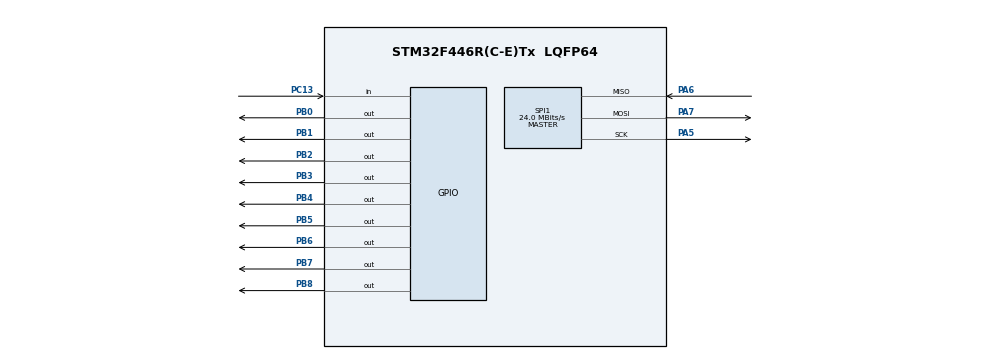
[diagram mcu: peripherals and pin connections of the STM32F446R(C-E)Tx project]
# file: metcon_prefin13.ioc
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Mcu.Family=STM32F4
Mcu.Name=STM32F446R(C-E)Tx
Mcu.Package=LQFP64
NVIC.PriorityGroup=NVIC_PRIORITYGROUP_4
PA5.Mode=Full_Duplex_Master
PA5.Signal=SPI1_SCK
PA6.Mode=Full_Duplex_Master
PA6.Signal=SPI1_MISO
PA7.Mode=Full_Duplex_Master
PA7.Signal=SPI1_MOSI
PB0.Signal=GPIO_Output
PB1.Signal=GPIO_Output
PB2.Signal=GPIO_Output
PB3.Signal=GPIO_Output
PB4.Signal=GPIO_Output
PB5.Signal=GPIO_Output
PB6.Signal=GPIO_Output
PB7.Signal=GPIO_Output
PB8.Signal=GPIO_Output
PC13.Signal=GPIO_Input
PH0-OSC_IN.Mode=HSE-External-Oscillator
PH0-OSC_IN.Signal=RCC_OSC_IN
PH1-OSC_OUT.Mode=HSE-External-Oscillator
PH1-OSC_OUT.Signal=RCC_OSC_OUT
ProjectManager.HeapSize=0x200
ProjectManager.StackSize=0x400
ProjectManager.TargetToolchain=STM32CubeIDE
RCC.AHBFreq_Value=48000000
RCC.APB1CLKDivider=RCC_HCLK_DIV2
RCC.APB1Freq_Value=24000000
RCC.APB1TimFreq_Value=48000000
RCC.APB2Freq_Value=48000000
RCC.APB2TimFreq_Value=48000000
RCC.CortexFreq_Value=48000000
RCC.HCLKFreq_Value=48000000
RCC.HSE_VALUE=8000000
RCC.PLLM=8
RCC.PLLP=RCC_PLLP_DIV4
RCC.PLLSourceVirtual=RCC_PLLSOURCE_HSE
RCC.SYSCLKFreq_VALUE=48000000
RCC.SYSCLKSource=RCC_SYSCLKSOURCE_PLLCLK
RCC.USBFreq_Value=96000000
RCC.VCOOutputFreq_Value=192000000
SPI1.CalculateBaudRate=24.0 MBits/s
SPI1.Direction=SPI_DIRECTION_2LINES
SPI1.Mode=SPI_MODE_MASTER
SPI1.VirtualType=VM_MASTER
board=custom

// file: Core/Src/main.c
/* USER CODE BEGIN Header */
/**
  ******************************************************************************
  * @file           : main.c
  * @brief          : Main program body
  ******************************************************************************
  * @attention
  *
  * Copyright (c) 2022 STMicroelectronics.
  * All rights reserved.
  *
  * This software is licensed under terms that can be found in the LICENSE file
  * in the root directory of this software component.
  * If no LICENSE file comes with this software, it is provided AS-IS.
  *
  ******************************************************************************
  */
/* USER CODE END Header */
#include "main.h"

/* USER CODE BEGIN Includes */
#include "functions.h"
#include "at45db_api.h"
/* USER CODE END Includes */

SPI_HandleTypeDef hspi1;

/* USER CODE BEGIN PV */
extern struct midi_msg incoming_note;
extern struct midi_msg incoming_CC_msg;
extern uint8_t msg_type;
extern uint8_t global_mode;

extern struct midi_msg incoming_note2;
extern struct midi_msg incoming_CC_msg2;
extern uint8_t msg_type2;

extern struct midi_msg seq_msg_list[WAITHEIGHT];					//array of sequencer messages need to be sensded.
extern uint8_t 		   seq_msg_push_index;
extern uint8_t 		   seq_msg_pop_index;
extern int 			   midi_access_semaph;
extern int 			   seq_list_flag;

/////////////////
extern struct midi_container 	sequencer_arr[SEQAMOUNT];				//array of sequencers
extern int 						seq_irq_cnt[SEQAMOUNT];

/* USER CODE END PV */

void SystemClock_Config(void);
static void MX_GPIO_Init(void);
static void MX_SPI1_Init(void);

int main(void)
{
  /* USER CODE BEGIN 1 */
	__disable_irq();
	SCB->VTOR = 0x08040000;
	__enable_irq();
  /* USER CODE END 1 */

  /* MCU Configuration--------------------------------------------------------*/

  /* Reset of all peripherals, Initializes the Flash interface and the Systick. */
  HAL_Init();

  /* Configure the system clock */
  SystemClock_Config();

  /* Initialize all configured peripherals */
  MX_GPIO_Init();
  MX_SPI1_Init();
  /* USER CODE BEGIN 2 */

  GPIO_Init();
  TIM1_Init_and_Start();
  EXTI_Init();
  usart1_init_and_start();
  usart2_init_and_start();
  usart3_init_and_start();
  usart4_init_and_start();

  GPIOB->ODR |= 1 << 9;  								//nWP   initial state
  GPIOB->ODR |= 1 << 10; 								//nCS   initial state

  global_mode_setting(); 								//endless cycle until user choose mode

  index_show_set();
  structures_init();

  /* USER CODE END 2 */

  /* Infinite loop */
  /* USER CODE BEGIN WHILE */
  while (1)
  {

	  // For Ornament Mode
	  for(int i = 0; i < SEQAMOUNT; i++)
	  {
		  if(seq_irq_cnt[i] > 0)
		  {
			  seq_irq_cnt[i]--;
			  real_pop_from_sequencer(&sequencer_arr[i], i);
		  }
	  }

	  empty_trig_queue(); // Эта очередь заполняется и секвенсором и сплиттером, когда отправляешь края диапазона

	  message_assambling();
	  if(incoming_note.complete_flag == 1)
	  {
		  incoming_note_processing(1);
	  }
	  if(incoming_CC_msg.complete_flag == 1)
	  {
		  incoming_CC_processing(1);
	  }

	  // Second midi in

	  message_assambling2();
	  if(incoming_note2.complete_flag == 1)
	  {
		  incoming_note_processing(2);
	  }
	  if(incoming_CC_msg2.complete_flag == 1)
	  {
		  incoming_CC_processing(2);
	  }

    /* USER CODE END WHILE */

  }
}

void SystemClock_Config(void)
{
  RCC_OscInitTypeDef RCC_OscInitStruct = {0};
  RCC_ClkInitTypeDef RCC_ClkInitStruct = {0};

  /** Configure the main internal regulator output voltage
  */
  __HAL_RCC_PWR_CLK_ENABLE();
  __HAL_PWR_VOLTAGESCALING_CONFIG(PWR_REGULATOR_VOLTAGE_SCALE3);
  /** Initializes the RCC Oscillators according to the specified parameters
  * in the RCC_OscInitTypeDef structure.
  */
  RCC_OscInitStruct.OscillatorType = RCC_OSCILLATORTYPE_HSE;
  RCC_OscInitStruct.HSEState = RCC_HSE_ON;
  RCC_OscInitStruct.PLL.PLLState = RCC_PLL_ON;
  RCC_OscInitStruct.PLL.PLLSource = RCC_PLLSOURCE_HSE;
  RCC_OscInitStruct.PLL.PLLM = 16; // 8 - for green, 16 - for black
  RCC_OscInitStruct.PLL.PLLN = 192;
  RCC_OscInitStruct.PLL.PLLP = RCC_PLLP_DIV4;
  RCC_OscInitStruct.PLL.PLLQ = 2;
  RCC_OscInitStruct.PLL.PLLR = 2;
  if (HAL_RCC_OscConfig(&RCC_OscInitStruct) != HAL_OK)
  {
    Error_Handler();
  }
  /** Initializes the CPU, AHB and APB buses clocks
  */
  RCC_ClkInitStruct.ClockType = RCC_CLOCKTYPE_HCLK|RCC_CLOCKTYPE_SYSCLK
                              |RCC_CLOCKTYPE_PCLK1|RCC_CLOCKTYPE_PCLK2;
  RCC_ClkInitStruct.SYSCLKSource = RCC_SYSCLKSOURCE_PLLCLK;
  RCC_ClkInitStruct.AHBCLKDivider = RCC_SYSCLK_DIV1;
  RCC_ClkInitStruct.APB1CLKDivider = RCC_HCLK_DIV2;
  RCC_ClkInitStruct.APB2CLKDivider = RCC_HCLK_DIV1;

  if (HAL_RCC_ClockConfig(&RCC_ClkInitStruct, FLASH_LATENCY_1) != HAL_OK)
  {
    Error_Handler();
  }
}

static void MX_SPI1_Init(void)
{

  /* SPI1 parameter configuration*/
  hspi1.Instance = SPI1;
  hspi1.Init.Mode = SPI_MODE_MASTER;
  hspi1.Init.Direction = SPI_DIRECTION_2LINES;
  hspi1.Init.DataSize = SPI_DATASIZE_8BIT;
  hspi1.Init.CLKPolarity = SPI_POLARITY_LOW;
  hspi1.Init.CLKPhase = SPI_PHASE_1EDGE;
  hspi1.Init.NSS = SPI_NSS_SOFT;
  hspi1.Init.BaudRatePrescaler = SPI_BAUDRATEPRESCALER_2;
  hspi1.Init.FirstBit = SPI_FIRSTBIT_MSB;
  hspi1.Init.TIMode = SPI_TIMODE_DISABLE;
  hspi1.Init.CRCCalculation = SPI_CRCCALCULATION_DISABLE;
  hspi1.Init.CRCPolynomial = 10;
  if (HAL_SPI_Init(&hspi1) != HAL_OK)
  {
    Error_Handler();
  }

}

static void MX_GPIO_Init(void)
{
  GPIO_InitTypeDef GPIO_InitStruct = {0};

  /* GPIO Ports Clock Enable */
  __HAL_RCC_GPIOC_CLK_ENABLE();
  __HAL_RCC_GPIOH_CLK_ENABLE();
  __HAL_RCC_GPIOA_CLK_ENABLE();
  __HAL_RCC_GPIOB_CLK_ENABLE();

  /*Configure GPIO pin Output Level */
  HAL_GPIO_WritePin(GPIOB, GPIO_PIN_0|GPIO_PIN_1|GPIO_PIN_2|GPIO_PIN_3
                          |GPIO_PIN_4|GPIO_PIN_5|GPIO_PIN_6|GPIO_PIN_7
                          |GPIO_PIN_8, GPIO_PIN_RESET);

  /*Configure GPIO pin : PC13 */
  GPIO_InitStruct.Pin = GPIO_PIN_13;
  GPIO_InitStruct.Mode = GPIO_MODE_INPUT;
  GPIO_InitStruct.Pull = GPIO_NOPULL;
  HAL_GPIO_Init(GPIOC, &GPIO_InitStruct);

  /*Configure GPIO pins : PB0 PB1 PB2 PB3
                           PB4 PB5 PB6 PB7
                           PB8 */
  GPIO_InitStruct.Pin = GPIO_PIN_0|GPIO_PIN_1|GPIO_PIN_2|GPIO_PIN_3
                          |GPIO_PIN_4|GPIO_PIN_5|GPIO_PIN_6|GPIO_PIN_7
                          |GPIO_PIN_8;
  GPIO_InitStruct.Mode = GPIO_MODE_OUTPUT_PP;
  GPIO_InitStruct.Pull = GPIO_NOPULL;
  GPIO_InitStruct.Speed = GPIO_SPEED_FREQ_LOW;
  HAL_GPIO_Init(GPIOB, &GPIO_InitStruct);

}

void Error_Handler(void)
{
  __disable_irq();
  while (1)
  {
  }
}
